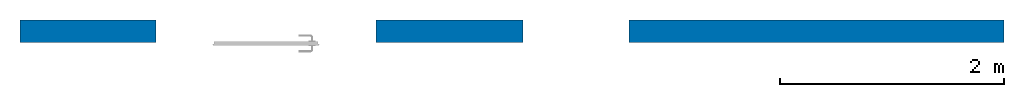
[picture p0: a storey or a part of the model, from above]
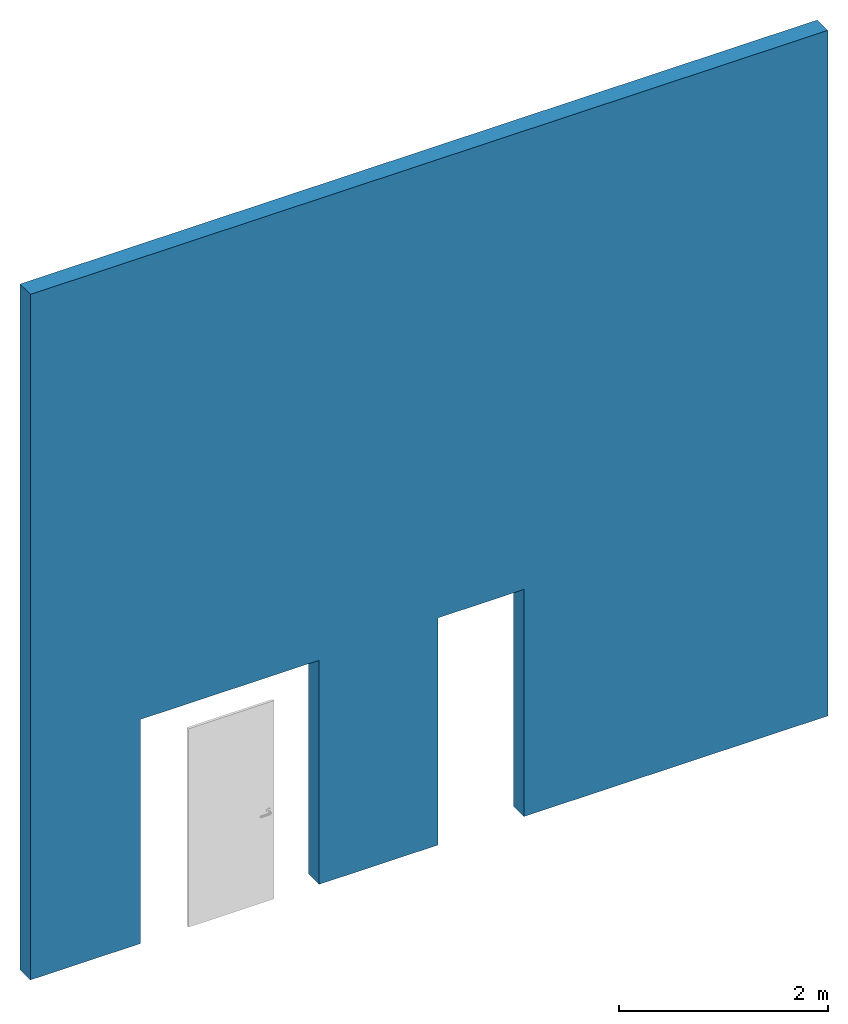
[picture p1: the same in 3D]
Properties of the parts of a building model (IFC2X3)

# File
Description: ViewDefinition [CoordinationView_V2.0]
File name: 0001
Time: 2018-10-07T12:32:25
Written by: The EXPRESS Data Manager Version 5.02.0100.07 : 28 Aug 2013
Made in: 20180328_1600(x64) - Exporter 19.1.0.0 - Alternate UI 19.1.0.0
Comment: STEP Physical File produced by: The EXPRESS Data Manager Version 5.02.0100.07 : 28 Aug 2013 * Module: EDMstepFileFactory/EDMstandAlone * Creation date: Sun Oct 07 12:32:25 2018 * Host: DESKTOP-FDA31SE * Database: C:\Users\marti\AppData\Local\Temp\{4A4F05A8-900B-4B34-8088-E3965E9843B5}\ifc * Database version: 5507 * Database creation date: Sun Oct 07 12:31:48 2018 * Schema: IFC2X3 * Model: DataRepository.ifc * Model creation date: Sun Oct 07 12:31:49 2018 * Header model: DataRepository.ifc_HeaderModel * Header model creation date: Sun Oct 07 12:31:49 2018 * EDMuser: sdai-user * EDMgroup: sdai-group * License ID and type: 5605 : Permanent license. Expiry date: * EDMstepFileFactory options: 020000

# IfcProject, 0001
LongName: Project Name; Phase: Project Status

# IfcSite, Default
RefLatitude: 42, 21, 30, 344238; RefLongitude: -71, -3, -35, -194702; RefElevation: 0 mm

# IfcBuilding
Pset_BuildingCommon - NumberOfStoreys: 1
Pset_ProductRequirements - Category: Project Information

# IfcBuildingStorey: Level:8mm Head, Level 1
LongName: Level 1; Elevation: 0 mm
Pset_AirSideSystemInformation - Name: Level 1
Pset_ProductRequirements - Name: Level 1; Category: Levels

# IfcDoor: opdek, voorbeeld 1_test_01_deurA:opdek:300951
In: Level 1
Type - OperationType: SINGLE_SWING_LEFT; ParameterTakesPrecedence: no; Sizeable: no; Material: Superlak
Type - voorbeeld 1_test_01_deurA:opdek:300951 - PanelOperation: SWINGING
OverallHeight: 2420 mm; OverallWidth: 1862 mm
Pset_DoorCommon - IsExternal: no; Reference: opdek
Pset_ProductRequirements - Category: Doors
Pset_QuantityTakeOff - Reference: opdek

# IfcDoor: voorbeeld 1_test_01_2315_930_2630_2000, voorbeeld 1_test_01:voorbeeld 1_test_01_2315_930_2630_2000:300948
In: Level 1
Type - ParameterTakesPrecedence: no; Sizeable: no; Material: Plastic, Opaque White, Glass, Glass, Clear Glazing
OverallHeight: 1970 mm; OverallWidth: 2615 mm
Pset_DoorCommon - IsExternal: yes; Reference: voorbeeld 1_test_01_2315_930_2630_2000
Pset_ManufacturerTypeInformation - Manufacturer: voorbeeld 1_test_01
Pset_ProductRequirements - Category: Doors
Pset_QuantityTakeOff - Reference: voorbeeld 1_test_01_2315_930_2630_2000

# IfcWallStandardCase: Basic Wall:Generic - 200mm, Basic Wall:Generic - 200mm:271706
In: Level 1
Type - PredefinedType: STANDARD; Material: Default Wall 200 mm
Type - Pset_ElementShading - Roughness: 914.4 mm
Type - Pset_ProductRequirements - Category: Walls
Type - Pset_QuantityTakeOff - Reference: Generic - 200mm
Type - Pset_ReinforcementBarPitchOfWall - Reference: Generic - 200mm
Type - Pset_WallCommon - Reference: Generic - 200mm; IsExternal: no
Pset_QuantityTakeOff - sets with these values: 2
Pset_WallCommon - IsExternal: yes; ExtendToStructure: no; LoadBearing: no
